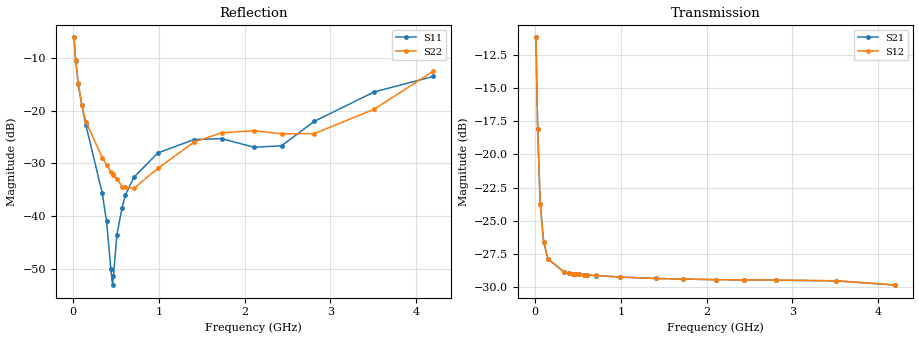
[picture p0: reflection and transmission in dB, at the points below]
! Integrated Device Technology
! Corporate Headquarters
! 6024 Silver Creek Valley Road
! San Jose, CA 95138  USA
! Phone:  1-408-284-8200
! Toll Free:  1-800-223-1366
! Webpage:  http://www.idt.com/
! Timing and RF Division
! 515 Groton Road, Suite 102
! Westford, MA 01886-6024
! Device:  F1950
! Description: 7-bit 0.25 dB Digital Step Attenuator
! Frequency:  150.0 -  4000.00 MHz
! Package:  4x4 mm Thin QFN Plastic Package: 24 pin
! Ports:  2 RF, 12 DC
!  Pin  1  = D0
!  Pin  2  = VDD
!  Pin  3  = Vmode
!  Pin  4  = GND
!  Pin  5  = RF1  =  Port 1
!  Pin  6  = GND
!  Pin  7  = GND
!  Pin  8  = GND
!  Pin  9  = GND
!  Pin 10  = GND
!  Pin 11  = GND
!  Pin 12  = GND
!  Pin 13  = GND
!  Pin 14  = RF2  =  Port 2
!  Pin 15  = GND
!  Pin 16  = LE
!  Pin 17  = CLK
!  Pin 18  = DATE
!  Pin 19  = D6
!  Pin 20  = D5
!  Pin 21  = D4
!  Pin 22  = D3
!  Pin 23  = D2
!  Pin 24  = D1
! State:  113
! Atten State:  28.25 dB
! Voltage:  +5.00 Volts
! Current:  Not Measured mA
! Data:  The device was measured on a the F195X evaluation board which has
!  individual transmission lines to the RF pins.  Data was collected
!  using a calibrated network analyzer.  The evaluation board was
!  de-embedded using a TRL calibration technique.
!  The reference plane is the edge of the package pin.
! Misc:  Board 2019
!  Action Tracker AT0250
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# GHz S dB R 50
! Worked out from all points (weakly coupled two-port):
!   420 points, 10 MHz to 4.2 GHz, reference 50 ohm
!   highest |S21| = -11.17 dB at 10 MHz (marker M1); lowest = -29.8 dB at 4.2 GHz (marker M2)
!   lowest |S11| = -53.1 dB at 460 MHz (marker M3), VSWR 1.00, Z = 49.8 - j0.0683 ohm
!   |S11| at or under -10 dB: 27.68 MHz to end of sweep
!   |S22| runs from -35.1 to -6.1 dB; largest |S21 - S12| = 8.6e-05
!   S11 on the Smith chart (normalised r, x): 10 MHz: 2.04, -1.26; 30 MHz: 1.26, -0.65; 60 MHz: 1.10, -0.37; 340 MHz: 1.01, -0.03; 4.2 GHz: 0.69, +0.17
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0.01  -6.09 -28.0  -11.17 -38.3  -11.17 -38.3  -6.07 -28.9
0.03  -10.47 -52.0  -18.05 -61.4  -18.05 -61.4  -10.43 -53.3
0.06  -14.96 -64.4  -23.75 -55.2  -23.75 -55.2  -14.76 -65.8
0.1  -18.84 -71.0  -26.61 -41.8  -26.61 -41.7  -18.84 -71.2
0.15  -22.80 -73.1  -27.87 -31.2  -27.87 -31.2  -22.10 -75.5
0.34  -35.70 -72.9  -28.87 -17.5  -28.87 -17.5  -28.93 -85.8
0.39  -41.02 -76.2  -28.93 -16.3  -28.93 -16.3  -30.27 -87.9
0.44  -50.06 -107.8  -28.99 -15.4  -28.98 -15.5  -31.67 -93.2
0.46  -53.13 -161.9  -29.00 -15.2  -29.00 -15.2  -32.07 -96.6
0.47  -51.49 171.6  -29.01 -15.1  -29.01 -15.1  -32.21 -98.3
0.51  -43.62 144.0  -29.03 -14.7  -29.03 -14.7  -32.91 -102.5
0.57  -38.49 136.9  -29.07 -14.3  -29.07 -14.3  -34.41 -113.3
0.61  -35.98 137.9  -29.09 -14.1  -29.09 -14.2  -34.53 -121.7
0.71  -32.61 138.6  -29.13 -14.0  -29.12 -14.0  -34.73 -141.4
0.99  -28.00 147.3  -29.24 -14.8  -29.24 -14.8  -30.92 178.9
1.41  -25.48 162.6  -29.35 -16.9  -29.35 -17.0  -25.97 159.8
1.73  -25.30 167.7  -29.39 -18.8  -29.39 -18.8  -24.20 151.4
2.11  -26.95 157.3  -29.44 -21.9  -29.44 -22.0  -23.80 141.5
2.43  -26.66 125.9  -29.46 -24.0  -29.45 -24.0  -24.38 130.6
2.81  -22.03 105.2  -29.48 -27.2  -29.47 -27.3  -24.36 115.2
3.51  -16.43 117.3  -29.53 -32.6  -29.52 -32.7  -19.72 112.7
4.2  -13.49 145.6  -29.85 -35.6  -29.84 -35.7  -12.47 126.9
